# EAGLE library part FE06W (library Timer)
FEMALE HEADER

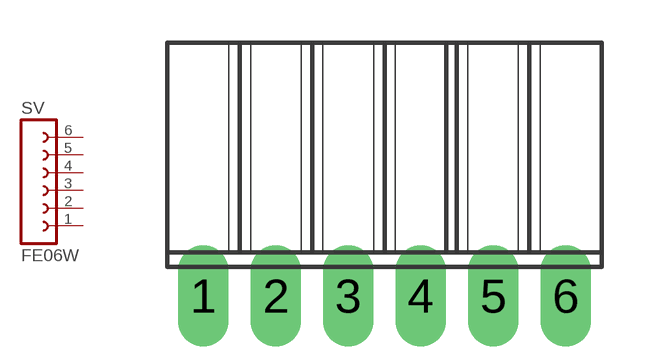
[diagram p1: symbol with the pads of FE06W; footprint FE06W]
Designator prefix SV

## FE06W (OC_FARNELL: unknown; OC_NEWARK: unknown)  [FE06W]
1  1  pas
2  2  pas
3  3  pas
4  4  pas
5  5  pas
6  6  pas

## Footprint FE06W (pad centres in mm)
FEMALE HEADER
drill 0.5 pad 1.778 long: 1 -6.35,0; 2 -3.81,0; 3 -1.27,0; 4 1.27,0; 5 3.81,0; 6 6.35,0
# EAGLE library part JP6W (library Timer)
HEADER 6-PIN 1-ROW 90-ANGLE HEADER

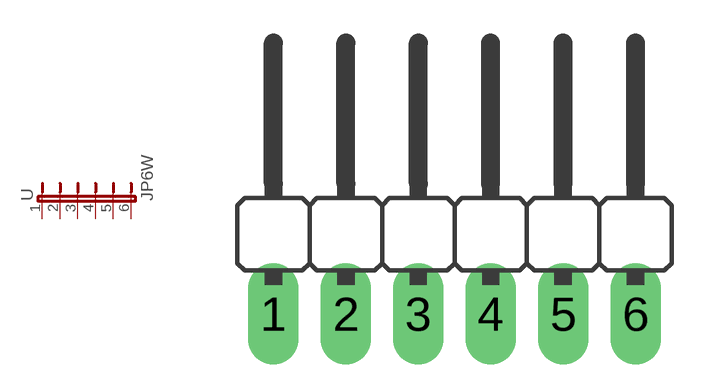
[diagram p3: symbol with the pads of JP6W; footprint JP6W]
Designator prefix -

## JP6W  [JP6W]
1  1  pas
2  2  pas
3  3  pas
4  4  pas
5  5  pas
6  6  pas

## Footprint JP6W (pad centres in mm)
grid 2.5, angle 90
drill 0.5 pad 1.778 long: 1 -6.35,-2.54; 2 -3.81,-2.54; 3 -1.27,-2.54; 4 1.27,-2.54; 5 3.81,-2.54; 6 6.35,-2.54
